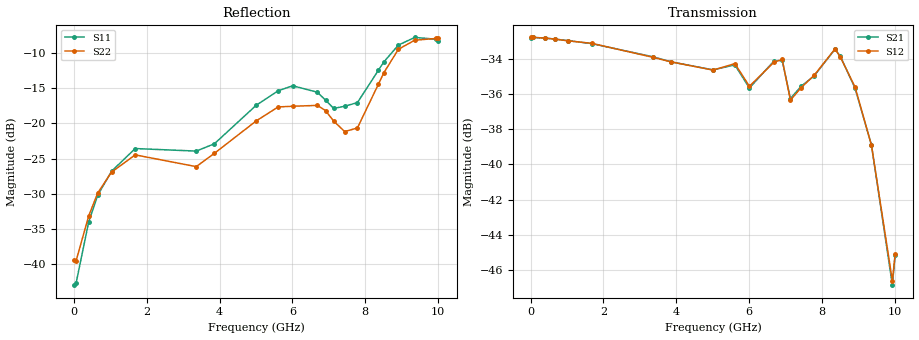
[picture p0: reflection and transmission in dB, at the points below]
! Device ID: PE43705
! Serial: 1
! Insertion: A
! Impedance: 50 ohm
! Temp: 25C
! VDD: 3.400V
! Attenuation Step: 31.75dB
#  Hz  S  RI  R  50
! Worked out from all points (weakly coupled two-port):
!   401 points, 10 MHz to 10.01 GHz, reference 50 ohm
!   highest |S21| = -32.77 dB at 60 MHz (marker M1); lowest = -46.9 dB at 9.935 GHz (marker M2)
!   lowest |S11| = -43.0 dB at 10 MHz (marker M3), VSWR 1.01, Z = 49.3 + j0.0455 ohm
!   |S11| at or under -10 dB: start of sweep to 8.692 GHz
!   |S22| runs from -39.5 to -7.8 dB; largest |S21 - S12| = 0.00073
!   S11 on the Smith chart (normalised r, x): 10 MHz: 0.99, +0.00; 7.435 GHz: 0.81, +0.15; 8.51 GHz: 0.82, +0.48; 9.36 GHz: 0.54, +0.48; 10.01 GHz: 0.48, +0.26
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1e7  -0.00708 0.000461  0.0229 -8.27e-05  0.023 -6.18e-05  -0.0107 0.000574
6e7  -0.00681 0.00259  0.023 -0.000328  0.023 -0.00035  -0.0101 0.00289
4.1e8  -0.0113 0.0166  0.0228 -0.00201  0.0228 -0.0021  -0.0135 0.0175
6.6e8  -0.0201 0.0236  0.0225 -0.0034  0.0225 -0.00335  -0.0204 0.0249
1.035e9  -0.0372 0.0266  0.0219 -0.0052  0.0219 -0.00512  -0.0344 0.0291
1.685e9  -0.0642 0.0165  0.0206 -0.00796  0.0206 -0.00805  -0.0553 0.0227
3.36e9  -0.0635 0.00327  0.0151 -0.0135  0.0151 -0.0134  -0.0467 0.0158
3.86e9  -0.0668 0.0261  0.0135 -0.0142  0.0136 -0.0141  -0.0542 0.0287
5.01e9  -0.1035 0.0864  0.0107 -0.0152  0.0108 -0.0151  -0.0865 0.0583
5.61e9  -0.1368 0.1017  0.00874 -0.0171  0.00889 -0.0172  -0.1121 0.0677
6.01e9  -0.1558 0.1001  0.0075 -0.0147  0.00754 -0.0149  -0.1157 0.0644
6.685e9  -0.1465 0.0792  0.00707 -0.0184  0.00689 -0.0183  -0.1237 0.0523
6.91e9  -0.1283 0.0707  0.00393 -0.0194  0.00398 -0.0195  -0.1132 0.049
7.135e9  -0.1156 0.0542  0.00302 -0.0151  0.0032 -0.0149  -0.0914 0.0491
7.435e9  -0.0949 0.0925  0.00411 -0.0162  0.00388 -0.0161  -0.0661 0.0574
7.785e9  -0.0495 0.1315  0.00443 -0.0173  0.00434 -0.0174  -0.0429 0.0823
8.36e9  -0.0164 0.2378  -0.00279 -0.0211  -0.0031 -0.0211  -0.0359 0.1862
8.51e9  -0.0253 0.2721  -0.00562 -0.0195  -0.00521 -0.0195  -0.0473 0.2239
8.91e9  -0.0801 0.3512  -0.009 -0.0138  -0.00894 -0.014  -0.114 0.3164
9.36e9  -0.1813 0.3662  -0.00813 -0.00795  -0.00808 -0.00797  -0.2136 0.3267
9.935e9  -0.3062 0.2518  -0.000813 -0.00446  -0.0006 -0.00462  -0.3526 0.1915
1.001e10  -0.3145 0.2276  0.000111 -0.00553  0.000456 -0.00553  -0.3671 0.1631
